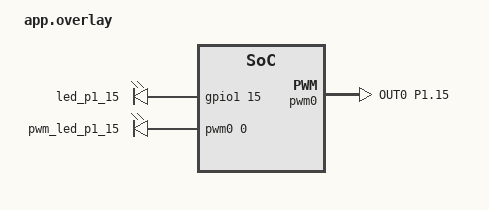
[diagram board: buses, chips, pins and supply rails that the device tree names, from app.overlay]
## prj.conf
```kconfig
CONFIG_GPIO=y
CONFIG_PWM=y
CONFIG_PRINTK=y
```

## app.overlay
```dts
#include <zephyr/dt-bindings/pwm/pwm.h>

/ {
    aliases {
        my-led = &led_p1_15;
        pwm-led0 = &pwm_led_p1_15;
    };

    leds {
        compatible = "gpio-leds";

        led_p1_15: led_p1_15 {
            gpios = <&gpio1 15 GPIO_ACTIVE_HIGH>;
        };
    };

    pwmleds {
        compatible = "pwm-leds";

        pwm_led_p1_15: pwm_led_p1_15 {
            pwms = <&pwm0 0 PWM_MSEC(1) PWM_POLARITY_NORMAL>;
        };
    };
};

&pinctrl {
    pwm0_default: pwm0_default {
        group1 {
            psels = <NRF_PSEL(PWM_OUT0, 1, 15)>;
        };
    };

    pwm0_sleep: pwm0_sleep {
        group1 {
            psels = <NRF_PSEL(PWM_OUT0, 1, 15)>;
            low-power-enable;
        };
    };
};

&pwm0 {
    status = "okay";
    pinctrl-0 = <&pwm0_default>;
    pinctrl-1 = <&pwm0_sleep>;
    pinctrl-names = "default", "sleep";
};
```

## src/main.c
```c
// LED unit test firmware (nRF52840 / Zephyr variant of code/code.ino):
//   Digital phase: blink P1.15; `value` tracks the pin through the resistor.
//   PWM phase: PWM at half duty -> `brightness` reports the duty;
//   full duty -> brightness must read 1; zero duty -> off.
#include <zephyr/kernel.h>
#include <zephyr/drivers/gpio.h>
#include <zephyr/drivers/pwm.h>
#include <zephyr/sys/printk.h>

static const struct gpio_dt_spec led = GPIO_DT_SPEC_GET(DT_ALIAS(my_led), gpios);
static const struct pwm_dt_spec pwm_led = PWM_DT_SPEC_GET(DT_ALIAS(pwm_led0));

int main(void)
{
    if (!gpio_is_ready_dt(&led) || !pwm_is_ready_dt(&pwm_led)) {
        printk("LED not ready\n");
        return 1;
    }
    gpio_pin_configure_dt(&led, GPIO_OUTPUT_ACTIVE);
    k_msleep(1000);
    gpio_pin_set_dt(&led, 0);
    k_msleep(1000);
    gpio_pin_set_dt(&led, 1);
    k_msleep(1000);
    gpio_pin_set_dt(&led, 0);
    k_msleep(1000);

    pwm_set_pulse_dt(&pwm_led, pwm_led.period / 2);
    k_msleep(1000);
    pwm_set_pulse_dt(&pwm_led, pwm_led.period);
    k_msleep(1000);
    pwm_set_pulse_dt(&pwm_led, 0);
    for (;;) {
        k_msleep(1000);
    }
    return 0;
}
```
